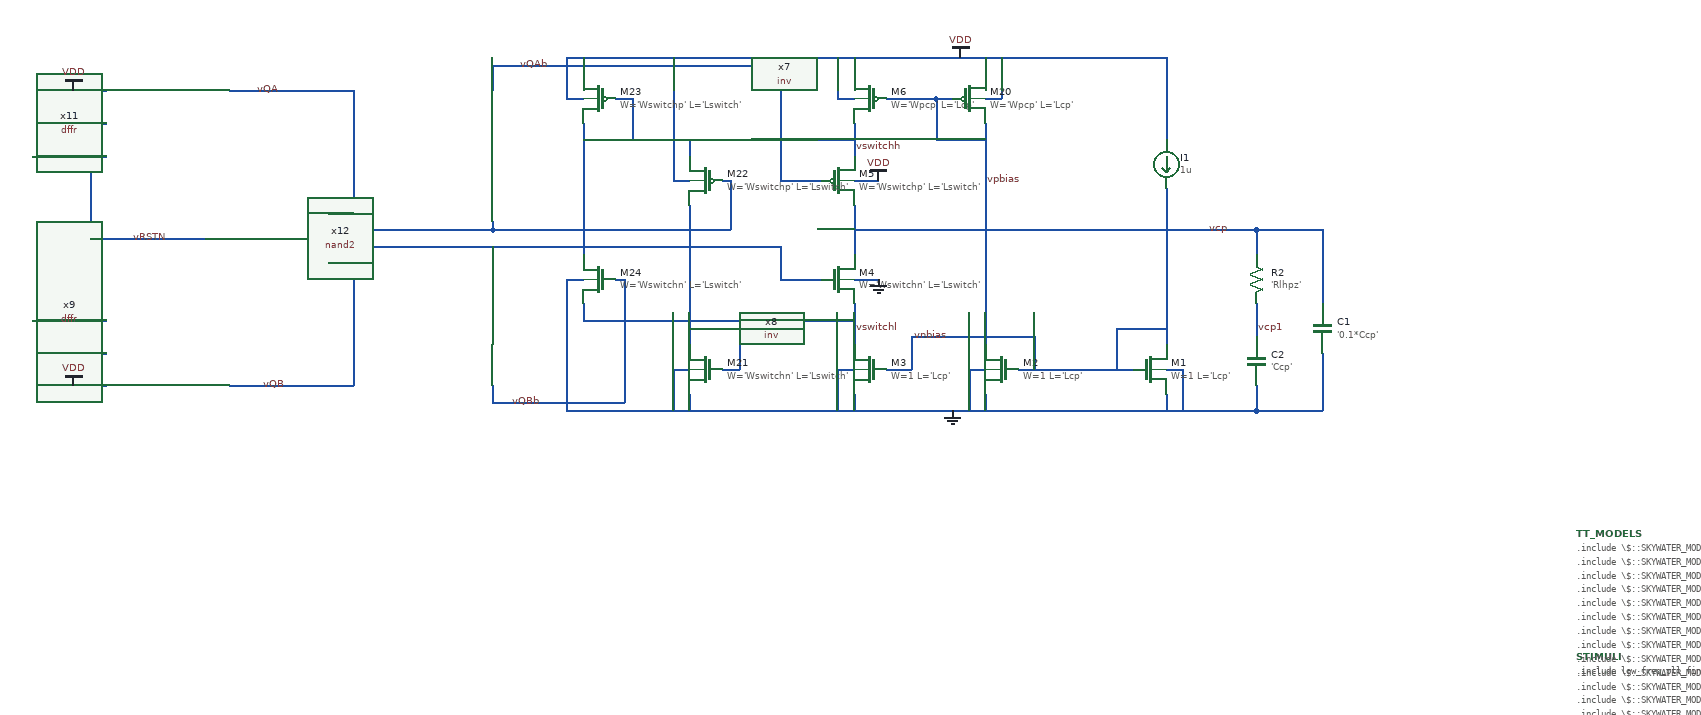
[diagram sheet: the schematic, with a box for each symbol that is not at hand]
v {xschem version=2.9.9 file_version=1.2 }
G {}
K {}
V {}
S {}
E {}
N -1440 -820 -1350 -820 { lab=vin_div}
N -1440 -1020 -1350 -1020 { lab=vsig_in}
N -1080 -890 -1050 -890 { lab=vQB}
N -280 -730 -280 -710 { lab=GND}
N -300 -760 -280 -760 { lab=GND}
N -300 -760 -300 -710 { lab=GND}
N -280 -1090 -260 -1090 { lab=VDD}
N -280 -1140 -280 -1120 { lab=VDD}
N -260 -1140 -260 -1090 { lab=VDD}
N -240 -760 -170 -760 { lab=vnbias}
N -340 -1090 -340 -1040 { lab=vpbias}
N -340 -1040 -280 -1040 { lab=vpbias}
N -340 -1090 -320 -1090 { lab=vpbias}
N -280 -1060 -280 -790 { lab=vpbias}
N -60 -730 -60 -710 { lab=GND}
N -60 -760 -40 -760 { lab=GND}
N -40 -760 -40 -710 { lab=GND}
N -400 -1090 -340 -1090 { lab=vpbias}
N -460 -1090 -440 -1090 { lab=VDD}
N -460 -1140 -460 -1090 { lab=VDD}
N -440 -1140 -440 -1120 { lab=VDD}
N -440 -730 -440 -710 { lab=GND}
N -460 -760 -440 -760 { lab=GND}
N -460 -760 -460 -710 { lab=GND}
N -220 -800 -220 -760 { lab=vnbias}
N -370 -800 -220 -800 { lab=vnbias}
N -370 -800 -370 -760 { lab=vnbias}
N -400 -760 -370 -760 { lab=vnbias}
N -440 -1060 -440 -1020 { lab=vswitchh}
N -440 -960 -440 -900 { lab=vcp}
N -440 -840 -440 -790 { lab=vswitchl}
N -440 -870 -410 -870 { lab=GND}
N -440 -990 -410 -990 { lab=VDD}
N -60 -1140 -60 -1040 { lab=VDD}
N -60 -980 -60 -790 { lab=vnbias}
N -120 -810 -60 -810 { lab=vnbias}
N -440 -930 -20 -930 { lab=vcp}
N -660 -990 -640 -990 { lab=VDD}
N -600 -760 -580 -760 { lab=#net1}
N -580 -810 -580 -760 { lab=#net1}
N -640 -810 -580 -810 { lab=#net1}
N -770 -840 -770 -820 { lab=vswitchl}
N -790 -870 -770 -870 { lab=GND}
N -790 -1090 -770 -1090 { lab=VDD}
N -790 -1140 -790 -1090 { lab=VDD}
N -770 -1140 -770 -1120 { lab=VDD}
N -660 -760 -640 -760 { lab=GND}
N -640 -730 -640 -710 { lab=GND}
N -660 -760 -660 -710 { lab=GND}
N -730 -1090 -710 -1090 { lab=#net2}
N -710 -1090 -710 -1040 { lab=#net2}
N -770 -1040 -710 -1040 { lab=#net2}
N -640 -1040 -440 -1040 { lab=vswitchh}
N -770 -820 -440 -820 { lab=vswitchl}
N -500 -990 -480 -990 { lab=vQAb}
N -600 -990 -590 -990 { lab=vQA}
N -500 -870 -480 -870 { lab=vQB}
N -730 -870 -720 -870 { lab=vQBb}
N -530 -990 -500 -990 { lab=vQAb}
N -530 -910 -530 -870 { lab=vQB}
N -530 -870 -500 -870 { lab=vQB}
N -640 -1040 -640 -1020 { lab=vswitchh}
N -640 -960 -640 -790 { lab=#net1}
N -660 -1140 -660 -990 { lab=VDD}
N -790 -870 -790 -710 { lab=GND}
N -770 -1060 -770 -900 { lab=#net2}
N -1200 -1100 -1050 -1100 { lab=vQA}
N -1200 -740 -1050 -740 { lab=vQB}
N -1370 -920 -1230 -920 { lab=vRSTN}
N -880 -1130 -880 -1100 { lab=vQAb}
N -880 -740 -880 -720 { lab=vQBb}
N -880 -940 -880 -930 { lab=vQA}
N -880 -910 -880 -900 { lab=vQB}
N -1050 -1100 -1050 -930 { lab=vQA}
N -1050 -930 -880 -930 { lab=vQA}
N -880 -1130 -530 -1130 { lab=vQAb}
N -530 -1130 -530 -990 { lab=vQAb}
N -880 -930 -590 -930 { lab=vQA}
N -590 -990 -590 -930 { lab=vQA}
N -1080 -950 -1050 -950 { lab=vQA}
N -1050 -910 -1050 -890 { lab=vQB}
N -1050 -910 -530 -910 { lab=vQB}
N -880 -720 -720 -720 { lab=vQBb}
N -720 -870 -720 -720 { lab=vQBb}
N -1370 -780 -1350 -780 { lab=vRSTN}
N -1370 -1060 -1370 -780 { lab=vRSTN}
N -1370 -1060 -1350 -1060 { lab=vRSTN}
N -1390 -1100 -1350 -1100 { lab=VDD}
N -1390 -740 -1350 -740 { lab=VDD}
N -1050 -890 -1050 -740 { lab=vQB}
N -170 -760 -100 -760 { lab=vnbias}
N -120 -810 -120 -760 { lab=vnbias}
N 50 -930 50 -900 { lab=vcp}
N 50 -740 50 -710 { lab=GND}
N 50 -840 50 -800 { lab=vcp1}
N -20 -930 50 -930 { lab=vcp}
N -790 -710 50 -710 { lab=GND}
N -790 -1140 -60 -1140 { lab=VDD}
N 50 -930 130 -930 { lab=vcp}
N 130 -930 130 -840 { lab=vcp}
N 130 -780 130 -710 { lab=GND}
N 50 -710 130 -710 { lab=GND}
C {devices/title.sym} 160 -30 0 0 {name=l1 author="Nikhil Poole"}
C {devices/code.sym} 440 -410 0 0 {name=STIMULI 
only_toplevel=true
place=end
value=".include low_freq_pll_final_commands.spice"}
C {devices/code.sym} 440 -560 0 0 {name=TT_MODELS
only_toplevel=true
format="tcleval( @value )"
value="
.include \\\\$::SKYWATER_MODELS\\\\/cells/nfet_01v8/sky130_fd_pr__nfet_01v8__tt.corner.spice
.include \\\\$::SKYWATER_MODELS\\\\/cells/nfet_01v8_lvt/sky130_fd_pr__nfet_01v8_lvt__tt.corner.spice
.include \\\\$::SKYWATER_MODELS\\\\/cells/pfet_01v8/sky130_fd_pr__pfet_01v8__tt.corner.spice
.include \\\\$::SKYWATER_MODELS\\\\/cells/nfet_03v3_nvt/sky130_fd_pr__nfet_03v3_nvt__tt.corner.spice
.include \\\\$::SKYWATER_MODELS\\\\/cells/nfet_05v0_nvt/sky130_fd_pr__nfet_05v0_nvt__tt.corner.spice
.include \\\\$::SKYWATER_MODELS\\\\/cells/esd_nfet_01v8/sky130_fd_pr__esd_nfet_01v8__tt.corner.spice
.include \\\\$::SKYWATER_MODELS\\\\/cells/pfet_01v8_lvt/sky130_fd_pr__pfet_01v8_lvt__tt.corner.spice
.include \\\\$::SKYWATER_MODELS\\\\/cells/pfet_01v8_hvt/sky130_fd_pr__pfet_01v8_hvt__tt.corner.spice
.include \\\\$::SKYWATER_MODELS\\\\/cells/esd_pfet_g5v0d10v5/sky130_fd_pr__esd_pfet_g5v0d10v5__tt.corner.spice
.include \\\\$::SKYWATER_MODELS\\\\/cells/pfet_g5v0d10v5/sky130_fd_pr__pfet_g5v0d10v5__tt.corner.spice
.include \\\\$::SKYWATER_MODELS\\\\/cells/pfet_g5v0d16v0/sky130_fd_pr__pfet_g5v0d16v0__tt.corner.spice
.include \\\\$::SKYWATER_MODELS\\\\/cells/nfet_g5v0d10v5/sky130_fd_pr__nfet_g5v0d10v5__tt.corner.spice
.include \\\\$::SKYWATER_MODELS\\\\/cells/nfet_g5v0d16v0/sky130_fd_pr__nfet_g5v0d16v0__tt_discrete.corner.spice
.include \\\\$::SKYWATER_MODELS\\\\/cells/esd_nfet_g5v0d10v5/sky130_fd_pr__esd_nfet_g5v0d10v5__tt.corner.spice
.include \\\\$::SKYWATER_MODELS\\\\/models/corners/tt/nonfet.spice
* Mismatch parameters
.include \\\\$::SKYWATER_MODELS\\\\/cells/nfet_01v8/sky130_fd_pr__nfet_01v8__mismatch.corner.spice
.include \\\\$::SKYWATER_MODELS\\\\/cells/pfet_01v8/sky130_fd_pr__pfet_01v8__mismatch.corner.spice
.include \\\\$::SKYWATER_MODELS\\\\/cells/nfet_01v8_lvt/sky130_fd_pr__nfet_01v8_lvt__mismatch.corner.spice
.include \\\\$::SKYWATER_MODELS\\\\/cells/pfet_01v8_lvt/sky130_fd_pr__pfet_01v8_lvt__mismatch.corner.spice
.include \\\\$::SKYWATER_MODELS\\\\/cells/pfet_01v8_hvt/sky130_fd_pr__pfet_01v8_hvt__mismatch.corner.spice
.include \\\\$::SKYWATER_MODELS\\\\/cells/nfet_g5v0d10v5/sky130_fd_pr__nfet_g5v0d10v5__mismatch.corner.spice
.include \\\\$::SKYWATER_MODELS\\\\/cells/pfet_g5v0d10v5/sky130_fd_pr__pfet_g5v0d10v5__mismatch.corner.spice
.include \\\\$::SKYWATER_MODELS\\\\/cells/nfet_05v0_nvt/sky130_fd_pr__nfet_05v0_nvt__mismatch.corner.spice
.include \\\\$::SKYWATER_MODELS\\\\/cells/nfet_03v3_nvt/sky130_fd_pr__nfet_03v3_nvt__mismatch.corner.spice
* Resistor\\\\$::SKYWATER_MODELS\\\\/Capacitor
.include \\\\$::SKYWATER_MODELS\\\\/models/r+c/res_typical__cap_typical.spice
.include \\\\$::SKYWATER_MODELS\\\\/models/r+c/res_typical__cap_typical__lin.spice
* Special cells
.include \\\\$::SKYWATER_MODELS\\\\/models/corners/tt/specialized_cells.spice
* All models
.include \\\\$::SKYWATER_MODELS\\\\/models/all.spice
* Corner
.include \\\\$::SKYWATER_MODELS\\\\/models/corners/tt/rf.spice
"}
C {devices/lab_wire.sym} -1380 -1020 0 0 {name=l2 sig_type=std_logic lab=vsig_in}
C {devices/lab_wire.sym} -1380 -820 0 0 {name=l3 sig_type=std_logic lab=vin_div}
C {devices/lab_wire.sym} -370 -800 0 1 {name=l5 sig_type=std_logic lab=vnbias}
C {devices/lab_wire.sym} -280 -990 0 1 {name=l6 sig_type=std_logic lab=vpbias}
C {devices/isource.sym} -60 -1010 0 1 {name=I1 value=1u}
C {sky130_fd_pr/nfet_01v8.sym} -80 -760 0 0 {name=M1
L='Lcp'
W=1
nf=1 
mult=100
ad="'int((nf+1)/2) * W/nf * 0.29'" 
pd="'2*int((nf+1)/2) * (W/nf + 0.29)'"
as="'int((nf+2)/2) * W/nf * 0.29'" 
ps="'2*int((nf+2)/2) * (W/nf + 0.29)'"
nrd="'0.29 / W'" nrs="'0.29 / W'"
sa=0 sb=0 sd=0
model=nfet_01v8
spiceprefix=X
}
C {sky130_fd_pr/nfet_01v8.sym} -260 -760 0 1 {name=M2
L='Lcp'
W=1
nf=1 
mult=1
ad="'int((nf+1)/2) * W/nf * 0.29'" 
pd="'2*int((nf+1)/2) * (W/nf + 0.29)'"
as="'int((nf+2)/2) * W/nf * 0.29'" 
ps="'2*int((nf+2)/2) * (W/nf + 0.29)'"
nrd="'0.29 / W'" nrs="'0.29 / W'"
sa=0 sb=0 sd=0
model=nfet_01v8
spiceprefix=X
}
C {sky130_fd_pr/nfet_01v8.sym} -420 -760 0 1 {name=M3
L='Lcp'
W=1
nf=1 
mult=1
ad="'int((nf+1)/2) * W/nf * 0.29'" 
pd="'2*int((nf+1)/2) * (W/nf + 0.29)'"
as="'int((nf+2)/2) * W/nf * 0.29'" 
ps="'2*int((nf+2)/2) * (W/nf + 0.29)'"
nrd="'0.29 / W'" nrs="'0.29 / W'"
sa=0 sb=0 sd=0
model=nfet_01v8
spiceprefix=X
}
C {sky130_fd_pr/nfet_01v8_lvt.sym} -460 -870 0 0 {name=M4
L='Lswitch'
W='Wswitchn'
nf=1
mult=1
ad="'int((nf+1)/2) * W/nf * 0.29'" 
pd="'2*int((nf+1)/2) * (W/nf + 0.29)'"
as="'int((nf+2)/2) * W/nf * 0.29'" 
ps="'2*int((nf+2)/2) * (W/nf + 0.29)'"
nrd="'0.29 / W'" nrs="'0.29 / W'"
sa=0 sb=0 sd=0
model=nfet_01v8_lvt
spiceprefix=X
}
C {sky130_fd_pr/pfet_01v8_lvt.sym} -460 -990 0 0 {name=M5
L='Lswitch'
W='Wswitchp'
nf=1
mult=1
ad="'int((nf+1)/2) * W/nf * 0.29'" 
pd="'2*int((nf+1)/2) * (W/nf + 0.29)'"
as="'int((nf+2)/2) * W/nf * 0.29'" 
ps="'2*int((nf+2)/2) * (W/nf + 0.29)'"
nrd="'0.29 / W'" nrs="'0.29 / W'"
sa=0 sb=0 sd=0
model=pfet_01v8_lvt
spiceprefix=X
}
C {devices/gnd.sym} -410 -870 0 0 {name=l7 lab=GND}
C {devices/gnd.sym} -320 -710 0 0 {name=l8 lab=GND}
C {devices/vdd.sym} -310 -1140 0 0 {name=l9 lab=VDD}
C {devices/vdd.sym} -410 -990 0 0 {name=l10 lab=VDD}
C {sky130_fd_pr/pfet_01v8.sym} -420 -1090 0 1 {name=M6
L='Lcp'
W='Wpcp'
nf=1
mult='Mpcp'
ad="'int((nf+1)/2) * W/nf * 0.29'" 
pd="'2*int((nf+1)/2) * (W/nf + 0.29)'"
as="'int((nf+2)/2) * W/nf * 0.29'" 
ps="'2*int((nf+2)/2) * (W/nf + 0.29)'"
nrd="'0.29 / W'" nrs="'0.29 / W'"
sa=0 sb=0 sd=0
model=pfet_01v8
spiceprefix=X
}
C {sky130_fd_pr/pfet_01v8.sym} -300 -1090 0 0 {name=M20
L='Lcp'
W='Wpcp'
nf=1
mult='Mpcp'
ad="'int((nf+1)/2) * W/nf * 0.29'" 
pd="'2*int((nf+1)/2) * (W/nf + 0.29)'"
as="'int((nf+2)/2) * W/nf * 0.29'" 
ps="'2*int((nf+2)/2) * (W/nf + 0.29)'"
nrd="'0.29 / W'" nrs="'0.29 / W'"
sa=0 sb=0 sd=0
model=pfet_01v8
spiceprefix=X
}
C {devices/capa.sym} 50 -770 0 0 {name=C2
m=1
value='Ccp'
footprint=1206
device="ceramic capacitor"}
C {devices/lab_wire.sym} -1130 -740 0 0 {name=l37 sig_type=std_logic lab=vQB}
C {devices/lab_wire.sym} -440 -1030 0 1 {name=l38 sig_type=std_logic lab=vswitchh}
C {devices/lab_wire.sym} -440 -810 0 1 {name=l39 sig_type=std_logic lab=vswitchl}
C {sky130_fd_pr/nfet_01v8.sym} -620 -760 0 1 {name=M21
L='Lswitch'
W='Wswitchn'
nf=1 
mult=1
ad="'int((nf+1)/2) * W/nf * 0.29'" 
pd="'2*int((nf+1)/2) * (W/nf + 0.29)'"
as="'int((nf+2)/2) * W/nf * 0.29'" 
ps="'2*int((nf+2)/2) * (W/nf + 0.29)'"
nrd="'0.29 / W'" nrs="'0.29 / W'"
sa=0 sb=0 sd=0
model=nfet_01v8
spiceprefix=X
}
C {sky130_fd_pr/pfet_01v8.sym} -620 -990 0 1 {name=M22
L='Lswitch'
W='Wswitchp'
nf=1
mult=1
ad="'int((nf+1)/2) * W/nf * 0.29'" 
pd="'2*int((nf+1)/2) * (W/nf + 0.29)'"
as="'int((nf+2)/2) * W/nf * 0.29'" 
ps="'2*int((nf+2)/2) * (W/nf + 0.29)'"
nrd="'0.29 / W'" nrs="'0.29 / W'"
sa=0 sb=0 sd=0
model=pfet_01v8
spiceprefix=X
}
C {devices/lab_wire.sym} -1170 -1100 0 1 {name=l40 sig_type=std_logic lab=vQA}
C {sky130_fd_pr/pfet_01v8.sym} -750 -1090 0 1 {name=M23
L='Lswitch'
W='Wswitchp'
nf=1
mult=1
ad="'int((nf+1)/2) * W/nf * 0.29'" 
pd="'2*int((nf+1)/2) * (W/nf + 0.29)'"
as="'int((nf+2)/2) * W/nf * 0.29'" 
ps="'2*int((nf+2)/2) * (W/nf + 0.29)'"
nrd="'0.29 / W'" nrs="'0.29 / W'"
sa=0 sb=0 sd=0
model=pfet_01v8
spiceprefix=X
}
C {sky130_fd_pr/nfet_01v8.sym} -750 -870 0 1 {name=M24
L='Lswitch'
W='Wswitchn'
nf=1 
mult=1
ad="'int((nf+1)/2) * W/nf * 0.29'" 
pd="'2*int((nf+1)/2) * (W/nf + 0.29)'"
as="'int((nf+2)/2) * W/nf * 0.29'" 
ps="'2*int((nf+2)/2) * (W/nf + 0.29)'"
nrd="'0.29 / W'" nrs="'0.29 / W'"
sa=0 sb=0 sd=0
model=nfet_01v8
spiceprefix=X
}
C {devices/lab_wire.sym} -820 -720 0 0 {name=l41 sig_type=std_logic lab=vQBb}
C {devices/lab_wire.sym} -10 -930 0 1 {name=l44 sig_type=std_logic lab=vcp}
C {devices/lab_wire.sym} -1320 -920 0 1 {name=l49 sig_type=std_logic lab=vRSTN}
C {/home/users/nhpoole/ee272b/ee272b_mixed_signal_mmwave_accelerator/designs/inv.sym} -880 -990 3 0 {name=x7 M=1}
C {/home/users/nhpoole/ee272b/ee272b_mixed_signal_mmwave_accelerator/designs/inv.sym} -880 -850 1 0 {name=x8 M=1}
C {devices/lab_wire.sym} -810 -1130 0 0 {name=l50 sig_type=std_logic lab=vQAb}
C {/home/users/nhpoole/ee272b/ee272b_mixed_signal_mmwave_accelerator/designs/dffr.sym} -1280 -780 2 1 {name=x9 M=1}
C {/home/users/nhpoole/ee272b/ee272b_mixed_signal_mmwave_accelerator/designs/dffr.sym} -1280 -1060 0 0 {name=x11 M=1}
C {devices/vdd.sym} -1390 -1100 0 0 {name=l51 lab=VDD}
C {devices/vdd.sym} -1390 -740 2 1 {name=l52 lab=VDD}
C {/home/users/nhpoole/ee272b/ee272b_mixed_signal_mmwave_accelerator/designs/nand2.sym} -1150 -920 0 1 {name=x12 M=1}
C {devices/res.sym} 50 -870 0 0 {name=R2
value='Rlhpz'
footprint=1206
device=resistor
m=1}
C {devices/noconn.sym} -1200 -820 0 1 {name=l11}
C {devices/noconn.sym} -1200 -1020 0 1 {name=l13}
C {devices/lab_wire.sym} 50 -810 0 1 {name=l4 sig_type=std_logic lab=vcp1}
C {devices/capa.sym} 130 -810 0 0 {name=C1
m=1
value='0.1*Ccp'
footprint=1206
device="ceramic capacitor"}
